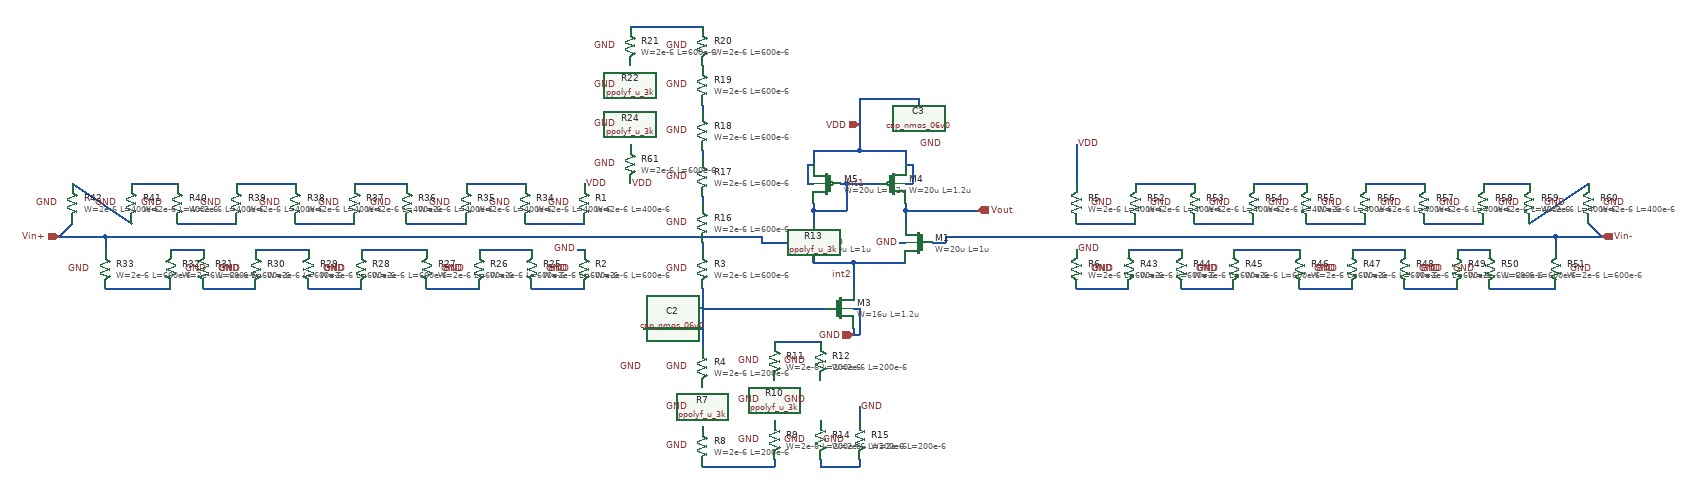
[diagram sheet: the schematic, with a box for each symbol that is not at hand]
v {xschem version=3.4.8RC file_version=1.3}
G {}
K {}
V {}
S {}
F {}
E {}
N 80 -50 80 -40 {lab=int2}
N 140 -40 210 -40 {lab=int2}
N 140 -40 140 0 {lab=int2}
N 80 -70 90 -70 {lab=GND}
N 210 -70 220 -70 {lab=GND}
N 140 30 150 30 {lab=GND}
N 140 60 140 70 {lab=GND}
N 150 30 150 70 {lab=GND}
N 140 70 150 70 {lab=GND}
N 210 -40 220 -40 {lab=int2}
N 70 -160 80 -160 {lab=VDD}
N 70 -190 70 -160 {lab=VDD}
N 70 -190 80 -190 {lab=VDD}
N 220 -160 230 -160 {lab=VDD}
N 230 -190 230 -160 {lab=VDD}
N 220 -190 230 -190 {lab=VDD}
N 80 -120 80 -100 {lab=int1}
N 220 -120 220 -100 {lab=Vout}
N 80 -210 80 -190 {lab=VDD}
N 150 -210 220 -210 {lab=VDD}
N 220 -210 220 -190 {lab=VDD}
N 130 -160 180 -160 {lab=int1}
N 130 -160 130 -120 {lab=int1}
N 80 -120 130 -120 {lab=int1}
N 220 -120 270 -120 {lab=Vout}
N 150 -250 150 -210 {lab=VDD}
N 0 -70 40 -70 {lab=Vin+}
N 90 -40 140 -40 {lab=int2}
N 80 -40 90 -40 {lab=int2}
N 120 -160 130 -160 {lab=int1}
N 80 -130 80 -120 {lab=int1}
N 220 -130 220 -120 {lab=Vout}
N 80 -210 150 -210 {lab=VDD}
N 270 -120 330 -120 {lab=Vout}
N -90 0 -90 90 {lab=#net1}
N -180 60 -90 60 {lab=#net1}
N -90 30 100 30 {lab=#net1}
N 150 -290 150 -250 {lab=VDD}
N 150 -290 240 -290 {lab=VDD}
N 240 -290 240 -280 {lab=VDD}
N 320 -80 470 -80 {lab=Vin-}
N 280 -80 320 -80 {lab=Vin-}
N 280 -80 280 -70 {lab=Vin-}
N -270 -80 -250 -80 {lab=Vin+}
N -250 -80 -210 -80 {lab=Vin+}
N -610 -80 -590 -80 {lab=Vin+}
N -590 -80 -270 -80 {lab=Vin+}
N -1000 -80 -610 -80 {lab=Vin+}
N -1000 -80 -1000 -60 {lab=Vin+}
N -1000 0 -900 0 {lab=#net2}
N -900 -60 -850 -60 {lab=#net3}
N -850 0 -770 0 {lab=#net4}
N -770 -60 -690 -60 {lab=#net5}
N -690 0 -610 0 {lab=#net6}
N -610 -60 -510 -60 {lab=#net7}
N -510 0 -430 0 {lab=#net8}
N -430 -60 -350 -60 {lab=#net9}
N -350 0 -270 0 {lab=#net10}
N -360 -100 -270 -100 {lab=#net11}
N -450 -160 -360 -160 {lab=#net12}
N -540 -100 -450 -100 {lab=#net13}
N -620 -160 -540 -160 {lab=#net14}
N -710 -100 -620 -100 {lab=#net15}
N -800 -160 -710 -160 {lab=#net16}
N -890 -100 -800 -100 {lab=#net17}
N -960 -160 -890 -160 {lab=#net18}
N -1050 -160 -960 -100 {lab=#net19}
N -1070 -80 -1050 -100 {lab=Vin+}
N -1070 -80 -1000 -80 {lab=Vin+}
N -280 -60 -270 -60 {lab=GND}
N -210 -80 0 -80 {lab=Vin+}
N 0 -80 0 -70 {lab=Vin+}
N 800 -80 820 -80 {lab=Vin-}
N 480 -80 800 -80 {lab=Vin-}
N 820 -80 1210 -80 {lab=Vin-}
N 1210 -80 1210 -60 {lab=Vin-}
N 1110 0 1210 0 {lab=#net20}
N 1060 -60 1110 -60 {lab=#net21}
N 980 0 1060 0 {lab=#net22}
N 900 -60 980 -60 {lab=#net23}
N 820 0 900 0 {lab=#net24}
N 720 -60 820 -60 {lab=#net25}
N 640 0 720 0 {lab=#net26}
N 560 -60 640 -60 {lab=#net27}
N 480 0 560 0 {lab=#net28}
N 480 -100 570 -100 {lab=#net29}
N 570 -160 660 -160 {lab=#net30}
N 660 -100 750 -100 {lab=#net31}
N 750 -160 830 -160 {lab=#net32}
N 830 -100 920 -100 {lab=#net33}
N 920 -160 1010 -160 {lab=#net34}
N 1010 -100 1100 -100 {lab=#net35}
N 1100 -160 1170 -160 {lab=#net36}
N 1170 -100 1260 -160 {lab=#net37}
N 1260 -100 1280 -80 {lab=Vin-}
N 1210 -80 1280 -80 {lab=Vin-}
N 480 -220 480 -160 {lab=VDD}
N 470 -80 480 -80 {lab=Vin-}
N -90 270 20 270 {lab=#net38}
N 20 260 20 270 {lab=#net38}
N 20 80 90 80 {lab=#net39}
N 90 260 90 270 {lab=#net40}
N 100 270 150 270 {lab=#net40}
N 150 260 150 270 {lab=#net40}
N 90 270 100 270 {lab=#net40}
N 150 180 150 200 {lab=GND}
N -90 -280 -90 -270 {lab=#net41}
N -90 -210 -90 -200 {lab=#net42}
N -90 -140 -90 -130 {lab=#net43}
N -200 -400 -90 -400 {lab=#net44}
N -90 -70 -90 -60 {lab=#net45}
N 260 -70 280 -70 {lab=Vin-}
C {symbols/nfet_05v0.sym} 240 -70 0 1 {name=M1
L=1u
W=20u
nf=10
m=1
ad="'int((nf+1)/2) * W/nf * 0.18u'"
pd="'2*int((nf+1)/2) * (W/nf + 0.18u)'"
as="'int((nf+2)/2) * W/nf * 0.18u'"
ps="'2*int((nf+2)/2) * (W/nf + 0.18u)'"
nrd="'0.18u / W'" nrs="'0.18u / W'"
sa=0 sb=0 sd=0
model=nfet_05v0
spiceprefix=X
}
C {symbols/nfet_05v0.sym} 60 -70 0 0 {name=M2
L=1u
W=20u
nf=10
m=1
ad="'int((nf+1)/2) * W/nf * 0.18u'"
pd="'2*int((nf+1)/2) * (W/nf + 0.18u)'"
as="'int((nf+2)/2) * W/nf * 0.18u'"
ps="'2*int((nf+2)/2) * (W/nf + 0.18u)'"
nrd="'0.18u / W'" nrs="'0.18u / W'"
sa=0 sb=0 sd=0
model=nfet_05v0
spiceprefix=X
}
C {symbols/nfet_05v0.sym} 120 30 0 0 {name=M3
L=1.2u
W=16u
nf=8
m=3
ad="'int((nf+1)/2) * W/nf * 0.18u'"
pd="'2*int((nf+1)/2) * (W/nf + 0.18u)'"
as="'int((nf+2)/2) * W/nf * 0.18u'"
ps="'2*int((nf+2)/2) * (W/nf + 0.18u)'"
nrd="'0.18u / W'" nrs="'0.18u / W'"
sa=0 sb=0 sd=0
model=nfet_05v0
spiceprefix=X
}
C {symbols/pfet_05v0.sym} 200 -160 0 0 {name=M4
L=1.2u
W=20u
nf=8
m=2
ad="'int((nf+1)/2) * W/nf * 0.18u'"
pd="'2*int((nf+1)/2) * (W/nf + 0.18u)'"
as="'int((nf+2)/2) * W/nf * 0.18u'"
ps="'2*int((nf+2)/2) * (W/nf + 0.18u)'"
nrd="'0.18u / W'" nrs="'0.18u / W'"
sa=0 sb=0 sd=0
model=pfet_05v0
spiceprefix=X
}
C {symbols/pfet_05v0.sym} 100 -160 0 1 {name=M5
L=1.2u
W=20u
nf=8
m=2
ad="'int((nf+1)/2) * W/nf * 0.18u'"
pd="'2*int((nf+1)/2) * (W/nf + 0.18u)'"
as="'int((nf+2)/2) * W/nf * 0.18u'"
ps="'2*int((nf+2)/2) * (W/nf + 0.18u)'"
nrd="'0.18u / W'" nrs="'0.18u / W'"
sa=0 sb=0 sd=0
model=pfet_05v0
spiceprefix=X
}
C {lab_wire.sym} 160 -160 0 0 {name=p2 sig_type=std_logic lab=int1
}
C {lab_wire.sym} 140 -20 0 0 {name=p3 sig_type=std_logic lab=int2
}
C {lab_pin.sym} 90 -70 0 1 {name=p9 sig_type=std_logic lab=GND}
C {lab_pin.sym} 210 -70 0 0 {name=p7 sig_type=std_logic lab=GND}
C {opin.sym} 330 -120 0 0 {name=p16 lab=Vout
}
C {symbols/ppolyf_u_3k.sym} -90 -30 0 0 {name=R3
W=2e-6
L=600e-6
model=ppolyf_u_3k
spiceprefix=X
m=1}
C {symbols/ppolyf_u_3k.sym} -90 120 0 0 {name=R4
W=2e-6
L=200e-6
model=ppolyf_u_3k
spiceprefix=X
m=1}
C {lab_pin.sym} -180 120 0 0 {name=p10 sig_type=std_logic lab=GND}
C {lab_pin.sym} -110 -30 0 0 {name=p11 sig_type=std_logic lab=GND}
C {lab_pin.sym} -110 120 0 0 {name=p12 sig_type=std_logic lab=GND}
C {lab_pin.sym} -200 -160 0 1 {name=p21 sig_type=std_logic lab=VDD}
C {symbols/cap_nmos_06v0.sym} 240 -250 0 0 {name=C3
W=30e-6
L=30e-6
model=cap_nmos_06v0
spiceprefix=X
m=4}
C {lab_pin.sym} 240 -220 0 1 {name=p20 sig_type=std_logic lab=GND}
C {symbols/ppolyf_u_3k.sym} -270 -130 0 0 {name=R1
W=2e-6
L=400e-6
model=ppolyf_u_3k
spiceprefix=X
m=1}
C {symbols/ppolyf_u_3k.sym} -270 -30 0 0 {name=R2
W=2e-6
L=600e-6
model=ppolyf_u_3k
spiceprefix=X
m=1}
C {lab_pin.sym} -280 -60 0 0 {name=p1 sig_type=std_logic lab=GND}
C {lab_pin.sym} -290 -130 0 0 {name=p15 sig_type=std_logic lab=GND}
C {lab_pin.sym} -290 -30 0 0 {name=p19 sig_type=std_logic lab=GND}
C {ipin.sym} -1070 -80 0 0 {name=p22 lab=Vin+}
C {symbols/ppolyf_u_3k.sym} -350 -30 2 0 {name=R25
W=2e-6
L=600e-6
model=ppolyf_u_3k
spiceprefix=X
m=1}
C {lab_pin.sym} -330 -30 2 0 {name=p38 sig_type=std_logic lab=GND}
C {symbols/ppolyf_u_3k.sym} -430 -30 0 0 {name=R26
W=2e-6
L=600e-6
model=ppolyf_u_3k
spiceprefix=X
m=1}
C {lab_pin.sym} -450 -30 0 0 {name=p39 sig_type=std_logic lab=GND}
C {symbols/ppolyf_u_3k.sym} -510 -30 2 0 {name=R27
W=2e-6
L=600e-6
model=ppolyf_u_3k
spiceprefix=X
m=1}
C {lab_pin.sym} -490 -30 2 0 {name=p40 sig_type=std_logic lab=GND}
C {symbols/ppolyf_u_3k.sym} -610 -30 0 0 {name=R28
W=2e-6
L=600e-6
model=ppolyf_u_3k
spiceprefix=X
m=1}
C {lab_pin.sym} -630 -30 0 0 {name=p41 sig_type=std_logic lab=GND}
C {symbols/ppolyf_u_3k.sym} -690 -30 2 0 {name=R29
W=2e-6
L=600e-6
model=ppolyf_u_3k
spiceprefix=X
m=1}
C {lab_pin.sym} -670 -30 2 0 {name=p42 sig_type=std_logic lab=GND}
C {symbols/ppolyf_u_3k.sym} -770 -30 0 0 {name=R30
W=2e-6
L=600e-6
model=ppolyf_u_3k
spiceprefix=X
m=1}
C {lab_pin.sym} -790 -30 0 0 {name=p43 sig_type=std_logic lab=GND}
C {symbols/ppolyf_u_3k.sym} -850 -30 2 0 {name=R31
W=2e-6
L=600e-6
model=ppolyf_u_3k
spiceprefix=X
m=1}
C {lab_pin.sym} -830 -30 2 0 {name=p44 sig_type=std_logic lab=GND}
C {lab_pin.sym} -880 -30 2 0 {name=p45 sig_type=std_logic lab=GND}
C {symbols/ppolyf_u_3k.sym} -900 -30 2 0 {name=R32
W=2e-6
L=600e-6
model=ppolyf_u_3k
spiceprefix=X
m=1}
C {lab_pin.sym} -1020 -30 0 0 {name=p46 sig_type=std_logic lab=GND}
C {symbols/ppolyf_u_3k.sym} -1000 -30 0 0 {name=R33
W=2e-6
L=600e-6
model=ppolyf_u_3k
spiceprefix=X
m=1}
C {symbols/ppolyf_u_3k.sym} -360 -130 0 0 {name=R34
W=2e-6
L=400e-6
model=ppolyf_u_3k
spiceprefix=X
m=1}
C {lab_pin.sym} -380 -130 0 0 {name=p47 sig_type=std_logic lab=GND}
C {symbols/ppolyf_u_3k.sym} -450 -130 0 0 {name=R35
W=2e-6
L=400e-6
model=ppolyf_u_3k
spiceprefix=X
m=1}
C {lab_pin.sym} -470 -130 0 0 {name=p48 sig_type=std_logic lab=GND}
C {symbols/ppolyf_u_3k.sym} -540 -130 0 0 {name=R36
W=2e-6
L=400e-6
model=ppolyf_u_3k
spiceprefix=X
m=1}
C {lab_pin.sym} -560 -130 0 0 {name=p49 sig_type=std_logic lab=GND}
C {symbols/ppolyf_u_3k.sym} -620 -130 0 0 {name=R37
W=2e-6
L=400e-6
model=ppolyf_u_3k
spiceprefix=X
m=1}
C {lab_pin.sym} -640 -130 0 0 {name=p50 sig_type=std_logic lab=GND}
C {symbols/ppolyf_u_3k.sym} -710 -130 0 0 {name=R38
W=2e-6
L=400e-6
model=ppolyf_u_3k
spiceprefix=X
m=1}
C {lab_pin.sym} -730 -130 0 0 {name=p51 sig_type=std_logic lab=GND}
C {symbols/ppolyf_u_3k.sym} -800 -130 0 0 {name=R39
W=2e-6
L=400e-6
model=ppolyf_u_3k
spiceprefix=X
m=1}
C {lab_pin.sym} -820 -130 0 0 {name=p52 sig_type=std_logic lab=GND}
C {symbols/ppolyf_u_3k.sym} -890 -130 0 0 {name=R40
W=2e-6
L=400e-6
model=ppolyf_u_3k
spiceprefix=X
m=1}
C {lab_pin.sym} -910 -130 0 0 {name=p53 sig_type=std_logic lab=GND}
C {symbols/ppolyf_u_3k.sym} -960 -130 0 0 {name=R41
W=2e-6
L=400e-6
model=ppolyf_u_3k
spiceprefix=X
m=1}
C {lab_pin.sym} -980 -130 0 0 {name=p54 sig_type=std_logic lab=GND}
C {symbols/ppolyf_u_3k.sym} -1050 -130 0 0 {name=R42
W=2e-6
L=400e-6
model=ppolyf_u_3k
spiceprefix=X
m=1}
C {lab_pin.sym} -1070 -130 0 0 {name=p55 sig_type=std_logic lab=GND}
C {lab_pin.sym} -270 -160 0 1 {name=p23 sig_type=std_logic lab=VDD}
C {ipin.sym} 1280 -80 0 1 {name=p13 lab=Vin-}
C {symbols/ppolyf_u_3k.sym} 480 -130 0 1 {name=R5
W=2e-6
L=400e-6
model=ppolyf_u_3k
spiceprefix=X
m=1}
C {symbols/ppolyf_u_3k.sym} 480 -30 0 1 {name=R6
W=2e-6
L=600e-6
model=ppolyf_u_3k
spiceprefix=X
m=1}
C {lab_pin.sym} 480 -60 0 1 {name=p14 sig_type=std_logic lab=GND}
C {lab_pin.sym} 500 -130 0 1 {name=p17 sig_type=std_logic lab=GND}
C {lab_pin.sym} 500 -30 0 1 {name=p18 sig_type=std_logic lab=GND}
C {symbols/ppolyf_u_3k.sym} 560 -30 2 1 {name=R43
W=2e-6
L=600e-6
model=ppolyf_u_3k
spiceprefix=X
m=1}
C {lab_pin.sym} 540 -30 2 1 {name=p56 sig_type=std_logic lab=GND}
C {symbols/ppolyf_u_3k.sym} 640 -30 0 1 {name=R44
W=2e-6
L=600e-6
model=ppolyf_u_3k
spiceprefix=X
m=1}
C {lab_pin.sym} 660 -30 0 1 {name=p57 sig_type=std_logic lab=GND}
C {symbols/ppolyf_u_3k.sym} 720 -30 2 1 {name=R45
W=2e-6
L=600e-6
model=ppolyf_u_3k
spiceprefix=X
m=1}
C {lab_pin.sym} 700 -30 2 1 {name=p58 sig_type=std_logic lab=GND}
C {symbols/ppolyf_u_3k.sym} 820 -30 0 1 {name=R46
W=2e-6
L=600e-6
model=ppolyf_u_3k
spiceprefix=X
m=1}
C {lab_pin.sym} 840 -30 0 1 {name=p59 sig_type=std_logic lab=GND}
C {symbols/ppolyf_u_3k.sym} 900 -30 2 1 {name=R47
W=2e-6
L=600e-6
model=ppolyf_u_3k
spiceprefix=X
m=1}
C {lab_pin.sym} 880 -30 2 1 {name=p60 sig_type=std_logic lab=GND}
C {symbols/ppolyf_u_3k.sym} 980 -30 0 1 {name=R48
W=2e-6
L=600e-6
model=ppolyf_u_3k
spiceprefix=X
m=1}
C {lab_pin.sym} 1000 -30 0 1 {name=p61 sig_type=std_logic lab=GND}
C {symbols/ppolyf_u_3k.sym} 1060 -30 2 1 {name=R49
W=2e-6
L=600e-6
model=ppolyf_u_3k
spiceprefix=X
m=1}
C {lab_pin.sym} 1040 -30 2 1 {name=p62 sig_type=std_logic lab=GND}
C {lab_pin.sym} 1090 -30 2 1 {name=p63 sig_type=std_logic lab=GND}
C {symbols/ppolyf_u_3k.sym} 1110 -30 2 1 {name=R50
W=2e-6
L=600e-6
model=ppolyf_u_3k
spiceprefix=X
m=1}
C {lab_pin.sym} 1230 -30 0 1 {name=p64 sig_type=std_logic lab=GND}
C {symbols/ppolyf_u_3k.sym} 1210 -30 0 1 {name=R51
W=2e-6
L=600e-6
model=ppolyf_u_3k
spiceprefix=X
m=1}
C {symbols/ppolyf_u_3k.sym} 570 -130 0 1 {name=R52
W=2e-6
L=400e-6
model=ppolyf_u_3k
spiceprefix=X
m=1}
C {lab_pin.sym} 590 -130 0 1 {name=p65 sig_type=std_logic lab=GND}
C {symbols/ppolyf_u_3k.sym} 660 -130 0 1 {name=R53
W=2e-6
L=400e-6
model=ppolyf_u_3k
spiceprefix=X
m=1}
C {lab_pin.sym} 680 -130 0 1 {name=p66 sig_type=std_logic lab=GND}
C {symbols/ppolyf_u_3k.sym} 750 -130 0 1 {name=R54
W=2e-6
L=400e-6
model=ppolyf_u_3k
spiceprefix=X
m=1}
C {lab_pin.sym} 770 -130 0 1 {name=p67 sig_type=std_logic lab=GND}
C {symbols/ppolyf_u_3k.sym} 830 -130 0 1 {name=R55
W=2e-6
L=400e-6
model=ppolyf_u_3k
spiceprefix=X
m=1}
C {lab_pin.sym} 850 -130 0 1 {name=p68 sig_type=std_logic lab=GND}
C {symbols/ppolyf_u_3k.sym} 920 -130 0 1 {name=R56
W=2e-6
L=400e-6
model=ppolyf_u_3k
spiceprefix=X
m=1}
C {lab_pin.sym} 940 -130 0 1 {name=p69 sig_type=std_logic lab=GND}
C {symbols/ppolyf_u_3k.sym} 1010 -130 0 1 {name=R57
W=2e-6
L=400e-6
model=ppolyf_u_3k
spiceprefix=X
m=1}
C {lab_pin.sym} 1030 -130 0 1 {name=p70 sig_type=std_logic lab=GND}
C {symbols/ppolyf_u_3k.sym} 1100 -130 0 1 {name=R58
W=2e-6
L=400e-6
model=ppolyf_u_3k
spiceprefix=X
m=1}
C {lab_pin.sym} 1120 -130 0 1 {name=p71 sig_type=std_logic lab=GND}
C {symbols/ppolyf_u_3k.sym} 1170 -130 0 1 {name=R59
W=2e-6
L=400e-6
model=ppolyf_u_3k
spiceprefix=X
m=1}
C {lab_pin.sym} 1190 -130 0 1 {name=p72 sig_type=std_logic lab=GND}
C {symbols/ppolyf_u_3k.sym} 1260 -130 0 1 {name=R60
W=2e-6
L=400e-6
model=ppolyf_u_3k
spiceprefix=X
m=1}
C {lab_pin.sym} 1280 -130 0 1 {name=p73 sig_type=std_logic lab=GND}
C {symbols/ppolyf_u_3k.sym} -90 180 0 0 {name=R7
W=2e-6
L=200e-6
model=ppolyf_u_3k
spiceprefix=X
m=1}
C {lab_pin.sym} -110 180 0 0 {name=p8 sig_type=std_logic lab=GND}
C {symbols/ppolyf_u_3k.sym} -90 240 0 0 {name=R8
W=2e-6
L=200e-6
model=ppolyf_u_3k
spiceprefix=X
m=1}
C {lab_pin.sym} -110 240 0 0 {name=p25 sig_type=std_logic lab=GND}
C {symbols/ppolyf_u_3k.sym} 20 230 0 0 {name=R9
W=2e-6
L=200e-6
model=ppolyf_u_3k
spiceprefix=X
m=1}
C {lab_pin.sym} 0 230 0 0 {name=p26 sig_type=std_logic lab=GND}
C {symbols/ppolyf_u_3k.sym} 20 170 0 0 {name=R10
W=2e-6
L=200e-6
model=ppolyf_u_3k
spiceprefix=X
m=1}
C {lab_pin.sym} 0 170 0 0 {name=p27 sig_type=std_logic lab=GND}
C {symbols/ppolyf_u_3k.sym} 20 110 0 0 {name=R11
W=2e-6
L=200e-6
model=ppolyf_u_3k
spiceprefix=X
m=1}
C {lab_pin.sym} 0 110 0 0 {name=p28 sig_type=std_logic lab=GND}
C {symbols/ppolyf_u_3k.sym} 90 110 0 0 {name=R12
W=2e-6
L=200e-6
model=ppolyf_u_3k
spiceprefix=X
m=1}
C {lab_pin.sym} 70 110 0 0 {name=p29 sig_type=std_logic lab=GND}
C {symbols/ppolyf_u_3k.sym} 90 170 0 0 {name=R13
W=2e-6
L=200e-6
model=ppolyf_u_3k
spiceprefix=X
m=1}
C {lab_pin.sym} 70 170 0 0 {name=p30 sig_type=std_logic lab=GND}
C {symbols/ppolyf_u_3k.sym} 90 230 0 0 {name=R14
W=2e-6
L=200e-6
model=ppolyf_u_3k
spiceprefix=X
m=1}
C {lab_pin.sym} 70 230 0 0 {name=p31 sig_type=std_logic lab=GND}
C {symbols/ppolyf_u_3k.sym} 150 230 0 0 {name=R15
W=2e-6
L=200e-6
model=ppolyf_u_3k
spiceprefix=X
m=1}
C {lab_pin.sym} 130 230 0 0 {name=p32 sig_type=std_logic lab=GND}
C {lab_pin.sym} 150 180 0 1 {name=p33 sig_type=std_logic lab=GND}
C {symbols/ppolyf_u_3k.sym} -90 -100 0 0 {name=R16
W=2e-6
L=600e-6
model=ppolyf_u_3k
spiceprefix=X
m=1}
C {symbols/ppolyf_u_3k.sym} -90 -170 0 0 {name=R17
W=2e-6
L=600e-6
model=ppolyf_u_3k
spiceprefix=X
m=1}
C {symbols/ppolyf_u_3k.sym} -90 -240 0 0 {name=R18
W=2e-6
L=600e-6
model=ppolyf_u_3k
spiceprefix=X
m=1}
C {symbols/ppolyf_u_3k.sym} -90 -310 0 0 {name=R19
W=2e-6
L=600e-6
model=ppolyf_u_3k
spiceprefix=X
m=1}
C {symbols/ppolyf_u_3k.sym} -90 -370 0 0 {name=R20
W=2e-6
L=600e-6
model=ppolyf_u_3k
spiceprefix=X
m=1}
C {symbols/ppolyf_u_3k.sym} -200 -370 0 0 {name=R21
W=2e-6
L=600e-6
model=ppolyf_u_3k
spiceprefix=X
m=1}
C {symbols/ppolyf_u_3k.sym} -200 -310 0 0 {name=R22
W=2e-6
L=600e-6
model=ppolyf_u_3k
spiceprefix=X
m=1}
C {symbols/ppolyf_u_3k.sym} -200 -250 0 0 {name=R24
W=2e-6
L=600e-6
model=ppolyf_u_3k
spiceprefix=X
m=1}
C {symbols/ppolyf_u_3k.sym} -200 -190 0 0 {name=R61
W=2e-6
L=600e-6
model=ppolyf_u_3k
spiceprefix=X
m=1}
C {lab_pin.sym} -110 -100 0 0 {name=p34 sig_type=std_logic lab=GND}
C {lab_pin.sym} -110 -170 0 0 {name=p35 sig_type=std_logic lab=GND}
C {lab_pin.sym} -110 -240 0 0 {name=p36 sig_type=std_logic lab=GND}
C {lab_pin.sym} -110 -310 0 0 {name=p37 sig_type=std_logic lab=GND}
C {lab_pin.sym} -110 -370 0 0 {name=p74 sig_type=std_logic lab=GND}
C {lab_pin.sym} -220 -370 0 0 {name=p75 sig_type=std_logic lab=GND}
C {lab_pin.sym} -220 -310 0 0 {name=p76 sig_type=std_logic lab=GND}
C {lab_pin.sym} -220 -250 0 0 {name=p77 sig_type=std_logic lab=GND}
C {lab_pin.sym} -220 -190 0 0 {name=p78 sig_type=std_logic lab=GND}
C {lab_pin.sym} 480 -220 0 1 {name=p6 sig_type=std_logic lab=VDD}
C {symbols/cap_nmos_06v0.sym} -180 90 0 0 {name=C2
W=30e-6
L=30e-6
model=cap_nmos_06v0
spiceprefix=X
m=4}
C {ipin.sym} 150 -250 0 0 {name=p24 lab=VDD}
C {ipin.sym} 140 70 0 0 {name=p79 lab=GND}
